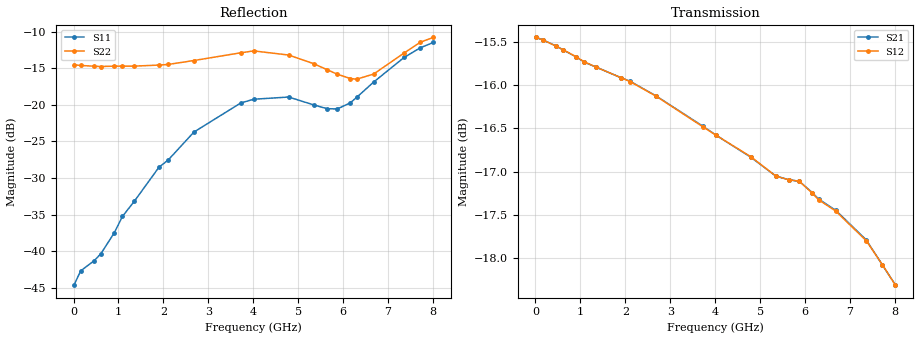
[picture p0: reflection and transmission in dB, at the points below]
! DEVICE ID: PE43712
! File Path: z:\PE43713\PE43713_CHAR_NOM_04292014\AMB\3p300\LS_ATT_14p25dB\PE43713_AMB_3p300V_3p000V_0p000V_LS_ATT_14p25dB_S2P_SN_10_A0139A.s2p
! Serial: 10
! Lot: A0139A
! Temp: 25C
! VDD: 3.300
! VSS: 0.000
! Control_Hi: 3.000
! Control_Lo: 0.000
! Attenuation Step: 14.25dB
! Port 1: RF1
! Port 2: RF2
! ThroughPath:1-2
! IDD: 0.0001472273
! ISS: -1.42e-007
#  Hz  S  RI  R  50
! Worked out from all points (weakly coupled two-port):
!   801 points, 10 MHz to 8.01 GHz, reference 50 ohm
!   highest |S21| = -15.45 dB at 10 MHz (marker M1); lowest = -18.3 dB at 8.01 GHz (marker M2)
!   lowest |S11| = -44.6 dB at 10 MHz (marker M3), VSWR 1.01, Z = 50.6 + j0.0438 ohm
!   |S11| at or under -10 dB: start of sweep to end of sweep
!   |S22| runs from -16.5 to -10.8 dB; largest |S21 - S12| = 0.0006
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1e7  0.00588 0.000433  0.1688 -0.000908  0.1688 -0.000871  -0.1876 0.00126
1.6e8  0.00701 0.0023  0.1679 -0.0112  0.1679 -0.0111  -0.1852 0.0124
4.6e8  0.00705 0.00502  0.164 -0.0308  0.164 -0.0307  -0.1807 0.0307
6.1e8  0.00648 0.00716  0.1612 -0.0399  0.1612 -0.0399  -0.1779 0.0407
9.1e8  0.00545 0.0123  0.1542 -0.0572  0.1542 -0.0573  -0.1736 0.0597
1.09e9  0.0054 0.0165  0.1491 -0.0667  0.1491 -0.0668  -0.1689 0.0718
1.35e9  0.00628 0.021  0.1413 -0.0798  0.1413 -0.0798  -0.162 0.0866
1.9e9  0.0117 0.0356  0.1211 -0.1046  0.1211 -0.1046  -0.1412 0.122
2.11e9  0.0141 0.0397  0.1123 -0.1129  0.1123 -0.1128  -0.1337 0.133
2.68e9  0.0255 0.06  0.0854 -0.1308  0.0853 -0.1308  -0.1031 0.172
3.72e9  0.0318 0.0978  0.0307 -0.1469  0.0306 -0.1468  -0.0678 0.216
4.01e9  0.0316 0.1045  0.0155 -0.1475  0.0154 -0.1475  -0.0638 0.2243
4.79e9  0.032 0.1084  -0.0233 -0.1421  -0.0233 -0.1422  -0.0422 0.2144
5.35e9  0.0431 0.09  -0.0482 -0.1319  -0.0482 -0.1319  -0.0206 0.1895
5.64e9  0.0534 0.0776  -0.06 -0.1262  -0.06 -0.1262  0.00186 0.1738
5.87e9  0.0633 0.0691  -0.0704 -0.1204  -0.0704 -0.1204  0.0233 0.1601
6.16e9  0.0813 0.0634  -0.0822 -0.1101  -0.0819 -0.1102  0.0555 0.1406
6.3e9  0.094 0.0613  -0.0863 -0.1054  -0.0861 -0.1054  0.0731 0.1304
6.68e9  0.1297 0.0602  -0.098 -0.0917  -0.0978 -0.0917  0.1203 0.1087
7.36e9  0.1984 0.0705  -0.1135 -0.0614  -0.1134 -0.0613  0.2014 0.102
7.72e9  0.2318 0.0794  -0.1162 -0.0456  -0.1162 -0.0457  0.2448 0.1074
8.01e9  0.2506 0.0901  -0.1167 -0.034  -0.1166 -0.0342  0.2667 0.1096
